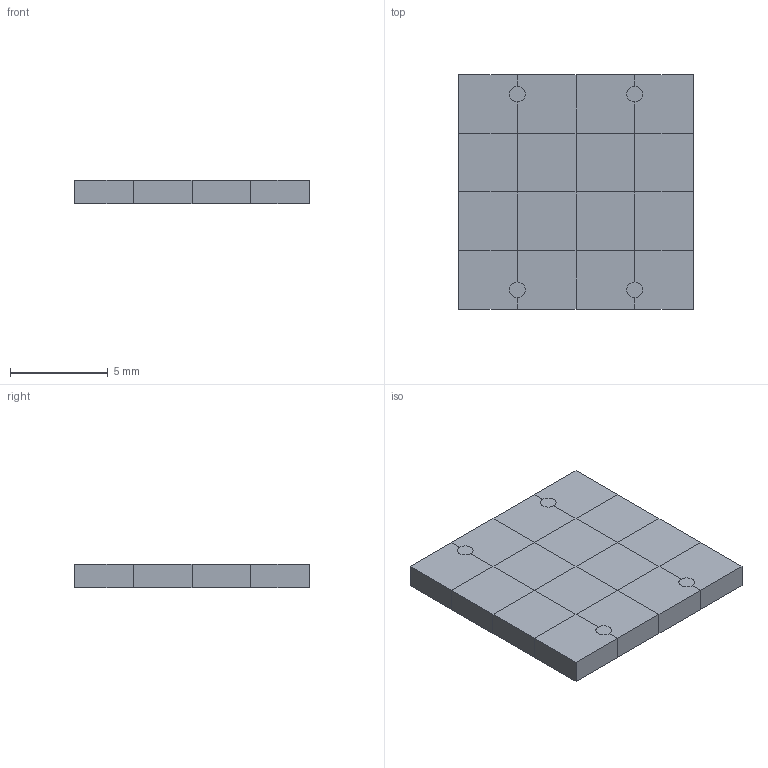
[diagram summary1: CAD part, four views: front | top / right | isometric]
STEP (ISO 10303-21) file: header records copied from the file, then geometry measured from it (millimetres).
FILE_DESCRIPTION(('Open CASCADE Model'),'2;1');
FILE_NAME('Open CASCADE Shape Model','2026-11-20T13:03:57',('Author'),( 'Open CASCADE'),'Open CASCADE STEP processor 7.9','Open CASCADE 7.9' ,'Unknown');
FILE_SCHEMA(('AUTOMOTIVE_DESIGN { 1 0 10303 214 1 1 1 1 }'));
Length unit declared in the file: millimetre
Products named in the file (3): manifold_AD_22-23_3; fluid; solid
Assembly tree (2 placements, depth 2):
  manifold_AD_22-23_3
    fluid
    solid
Bounding box: 12 x 12 x 1.2 mm (x, y, z)
Volume: 172.8 mm3; surface area: 1354.6 mm2
Topology: 2 solids, 2 shells, 860 faces, 3108 edges, 1722 vertices
Faces by surface type: plane 852, cylinder 8
Full cylindrical faces by diameter (mm): 0.8 x8
Entity records: 72718 total; most frequent: CARTESIAN_POINT 11957, DIRECTION 11066, LINE 9276, VECTOR 9276, ORIENTED_EDGE 6216, PCURVE 6216, DEFINITIONAL_REPRESENTATION 6216, EDGE_CURVE 3108
One B-rep face of a CAD part: STEP entity #38586.
In plain terms, the planar face has unit normal (0, 0, 1).
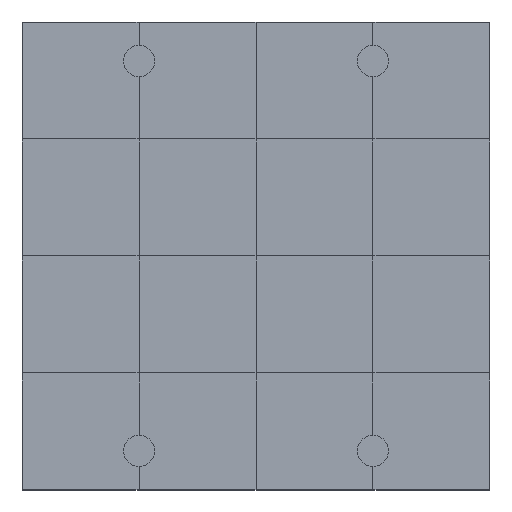
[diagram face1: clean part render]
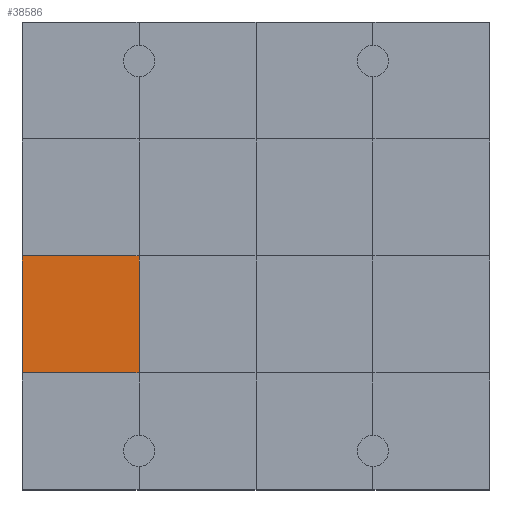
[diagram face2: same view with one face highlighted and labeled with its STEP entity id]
Its self-contained STEP definition (entity closure, numbers rounded to 3 decimals):
#38136 = VERTEX_POINT('',#38137);
#38137 = CARTESIAN_POINT('',(0.,3.,1.2));
#38151 = PLANE('',#38152);
#38152 = AXIS2_PLACEMENT_3D('',#38153,#38154,#38155);
#38153 = CARTESIAN_POINT('',(0.,3.,0.));
#38154 = DIRECTION('',(1.,0.,-0.));
#38155 = DIRECTION('',(0.,0.,1.));
#38177 = PLANE('',#38178);
#38178 = AXIS2_PLACEMENT_3D('',#38179,#38180,#38181);
#38179 = CARTESIAN_POINT('',(0.,0.,1.2));
#38180 = DIRECTION('',(0.,0.,1.));
#38181 = DIRECTION('',(1.,0.,-0.));
#38328 = VERTEX_POINT('',#38329);
#38329 = CARTESIAN_POINT('',(3.,3.,1.2));
#38350 = EDGE_CURVE('',#38136,#38328,#38351,.T.);
#38351 = SURFACE_CURVE('',#38352,(#38356,#38363),.PCURVE_S1.);
#38352 = LINE('',#38353,#38354);
#38353 = CARTESIAN_POINT('',(0.,3.,1.2));
#38354 = VECTOR('',#38355,1.);
#38355 = DIRECTION('',(1.,0.,-0.));
#38356 = PCURVE('',#38177,#38357);
#38357 = DEFINITIONAL_REPRESENTATION('',(#38358),#38362);
#38358 = LINE('',#38359,#38360);
#38359 = CARTESIAN_POINT('',(0.,3.));
#38360 = VECTOR('',#38361,1.);
#38361 = DIRECTION('',(1.,0.));
#38362 = ( GEOMETRIC_REPRESENTATION_CONTEXT(2) 
PARAMETRIC_REPRESENTATION_CONTEXT() REPRESENTATION_CONTEXT('2D SPACE',''
  ) );
#38363 = PCURVE('',#38364,#38369);
#38364 = PLANE('',#38365);
#38365 = AXIS2_PLACEMENT_3D('',#38366,#38367,#38368);
#38366 = CARTESIAN_POINT('',(0.,3.,1.2));
#38367 = DIRECTION('',(0.,0.,1.));
#38368 = DIRECTION('',(1.,0.,-0.));
#38369 = DEFINITIONAL_REPRESENTATION('',(#38370),#38374);
#38370 = LINE('',#38371,#38372);
#38371 = CARTESIAN_POINT('',(0.,0.));
#38372 = VECTOR('',#38373,1.);
#38373 = DIRECTION('',(1.,0.));
#38374 = ( GEOMETRIC_REPRESENTATION_CONTEXT(2) 
PARAMETRIC_REPRESENTATION_CONTEXT() REPRESENTATION_CONTEXT('2D SPACE',''
  ) );
#38409 = VERTEX_POINT('',#38410);
#38410 = CARTESIAN_POINT('',(0.,6.,1.2));
#38436 = EDGE_CURVE('',#38136,#38409,#38437,.T.);
#38437 = SURFACE_CURVE('',#38438,(#38442,#38449),.PCURVE_S1.);
#38438 = LINE('',#38439,#38440);
#38439 = CARTESIAN_POINT('',(0.,3.,1.2));
#38440 = VECTOR('',#38441,1.);
#38441 = DIRECTION('',(-0.,1.,0.));
#38442 = PCURVE('',#38151,#38443);
#38443 = DEFINITIONAL_REPRESENTATION('',(#38444),#38448);
#38444 = LINE('',#38445,#38446);
#38445 = CARTESIAN_POINT('',(1.2,0.));
#38446 = VECTOR('',#38447,1.);
#38447 = DIRECTION('',(0.,-1.));
#38448 = ( GEOMETRIC_REPRESENTATION_CONTEXT(2) 
PARAMETRIC_REPRESENTATION_CONTEXT() REPRESENTATION_CONTEXT('2D SPACE',''
  ) );
#38449 = PCURVE('',#38364,#38450);
#38450 = DEFINITIONAL_REPRESENTATION('',(#38451),#38455);
#38451 = LINE('',#38452,#38453);
#38452 = CARTESIAN_POINT('',(0.,0.));
#38453 = VECTOR('',#38454,1.);
#38454 = DIRECTION('',(0.,1.));
#38455 = ( GEOMETRIC_REPRESENTATION_CONTEXT(2) 
PARAMETRIC_REPRESENTATION_CONTEXT() REPRESENTATION_CONTEXT('2D SPACE',''
  ) );
#38586 = ADVANCED_FACE('',(#38587),#38364,.T.);
#38587 = FACE_BOUND('',#38588,.T.);
#38588 = EDGE_LOOP('',(#38589,#38590,#38591,#38619));
#38589 = ORIENTED_EDGE('',*,*,#38436,.F.);
#38590 = ORIENTED_EDGE('',*,*,#38350,.T.);
#38591 = ORIENTED_EDGE('',*,*,#38592,.T.);
#38592 = EDGE_CURVE('',#38328,#38593,#38595,.T.);
#38593 = VERTEX_POINT('',#38594);
#38594 = CARTESIAN_POINT('',(3.,6.,1.2));
#38595 = SURFACE_CURVE('',#38596,(#38600,#38607),.PCURVE_S1.);
#38596 = LINE('',#38597,#38598);
#38597 = CARTESIAN_POINT('',(3.,3.,1.2));
#38598 = VECTOR('',#38599,1.);
#38599 = DIRECTION('',(-0.,1.,0.));
#38600 = PCURVE('',#38364,#38601);
#38601 = DEFINITIONAL_REPRESENTATION('',(#38602),#38606);
#38602 = LINE('',#38603,#38604);
#38603 = CARTESIAN_POINT('',(3.,0.));
#38604 = VECTOR('',#38605,1.);
#38605 = DIRECTION('',(0.,1.));
#38606 = ( GEOMETRIC_REPRESENTATION_CONTEXT(2) 
PARAMETRIC_REPRESENTATION_CONTEXT() REPRESENTATION_CONTEXT('2D SPACE',''
  ) );
#38607 = PCURVE('',#38608,#38613);
#38608 = PLANE('',#38609);
#38609 = AXIS2_PLACEMENT_3D('',#38610,#38611,#38612);
#38610 = CARTESIAN_POINT('',(3.,3.,1.2));
#38611 = DIRECTION('',(0.,0.,1.));
#38612 = DIRECTION('',(1.,0.,-0.));
#38613 = DEFINITIONAL_REPRESENTATION('',(#38614),#38618);
#38614 = LINE('',#38615,#38616);
#38615 = CARTESIAN_POINT('',(0.,0.));
#38616 = VECTOR('',#38617,1.);
#38617 = DIRECTION('',(0.,1.));
#38618 = ( GEOMETRIC_REPRESENTATION_CONTEXT(2) 
PARAMETRIC_REPRESENTATION_CONTEXT() REPRESENTATION_CONTEXT('2D SPACE',''
  ) );
#38619 = ORIENTED_EDGE('',*,*,#38620,.F.);
#38620 = EDGE_CURVE('',#38409,#38593,#38621,.T.);
#38621 = SURFACE_CURVE('',#38622,(#38626,#38633),.PCURVE_S1.);
#38622 = LINE('',#38623,#38624);
#38623 = CARTESIAN_POINT('',(0.,6.,1.2));
#38624 = VECTOR('',#38625,1.);
#38625 = DIRECTION('',(1.,0.,-0.));
#38626 = PCURVE('',#38364,#38627);
#38627 = DEFINITIONAL_REPRESENTATION('',(#38628),#38632);
#38628 = LINE('',#38629,#38630);
#38629 = CARTESIAN_POINT('',(0.,3.));
#38630 = VECTOR('',#38631,1.);
#38631 = DIRECTION('',(1.,0.));
#38632 = ( GEOMETRIC_REPRESENTATION_CONTEXT(2) 
PARAMETRIC_REPRESENTATION_CONTEXT() REPRESENTATION_CONTEXT('2D SPACE',''
  ) );
#38633 = PCURVE('',#38634,#38639);
#38634 = PLANE('',#38635);
#38635 = AXIS2_PLACEMENT_3D('',#38636,#38637,#38638);
#38636 = CARTESIAN_POINT('',(0.,6.,1.2));
#38637 = DIRECTION('',(0.,0.,1.));
#38638 = DIRECTION('',(1.,0.,-0.));
#38639 = DEFINITIONAL_REPRESENTATION('',(#38640),#38644);
#38640 = LINE('',#38641,#38642);
#38641 = CARTESIAN_POINT('',(0.,0.));
#38642 = VECTOR('',#38643,1.);
#38643 = DIRECTION('',(1.,0.));
#38644 = ( GEOMETRIC_REPRESENTATION_CONTEXT(2) 
PARAMETRIC_REPRESENTATION_CONTEXT() REPRESENTATION_CONTEXT('2D SPACE',''
  ) );
